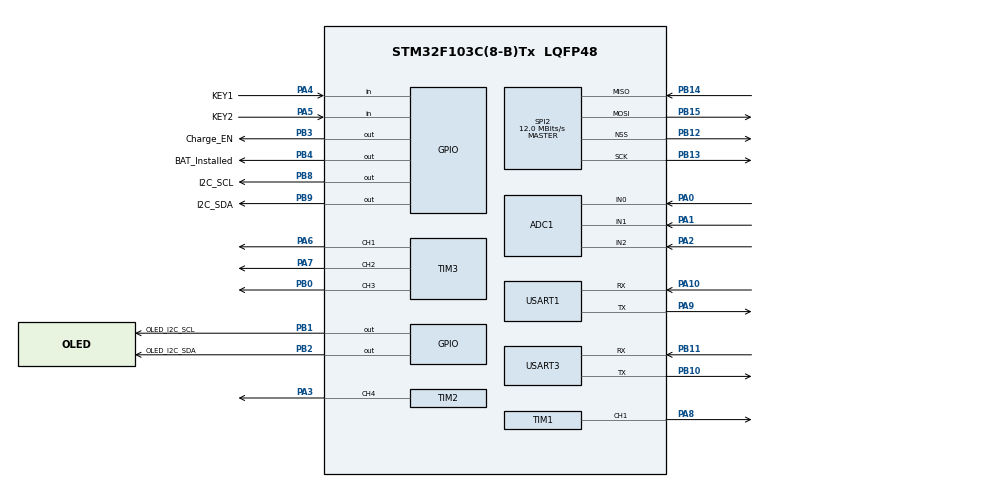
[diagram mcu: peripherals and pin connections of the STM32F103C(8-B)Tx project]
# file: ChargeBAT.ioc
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ADC1.Channel-0\#ChannelRegularConversion=ADC_CHANNEL_0
ADC1.Channel-1\#ChannelRegularConversion=ADC_CHANNEL_1
ADC1.Channel-2\#ChannelRegularConversion=ADC_CHANNEL_2
ADC1.ContinuousConvMode=DISABLE
ADC1.NbrOfConversion=3
ADC1.NbrOfConversionFlag=1
ADC1.Rank-0\#ChannelRegularConversion=1
ADC1.Rank-1\#ChannelRegularConversion=2
ADC1.Rank-2\#ChannelRegularConversion=3
ADC1.SamplingTime-0\#ChannelRegularConversion=ADC_SAMPLETIME_71CYCLES_5
ADC1.SamplingTime-1\#ChannelRegularConversion=ADC_SAMPLETIME_71CYCLES_5
ADC1.SamplingTime-2\#ChannelRegularConversion=ADC_SAMPLETIME_71CYCLES_5
ADC1.master=1
Dma.ADC1.3.Direction=DMA_PERIPH_TO_MEMORY
Dma.ADC1.3.Instance=DMA1_Channel1
Dma.ADC1.3.MemDataAlignment=DMA_MDATAALIGN_HALFWORD
Dma.ADC1.3.MemInc=DMA_MINC_ENABLE
Dma.ADC1.3.Mode=DMA_NORMAL
Dma.ADC1.3.PeriphDataAlignment=DMA_PDATAALIGN_HALFWORD
Dma.ADC1.3.PeriphInc=DMA_PINC_DISABLE
Dma.ADC1.3.Priority=DMA_PRIORITY_LOW
Dma.Request0=SPI2_TX
Dma.Request1=USART3_RX
Dma.Request2=USART1_TX
Dma.Request3=ADC1
Dma.SPI2_TX.0.Direction=DMA_MEMORY_TO_PERIPH
Dma.SPI2_TX.0.Instance=DMA1_Channel5
Dma.SPI2_TX.0.MemDataAlignment=DMA_MDATAALIGN_BYTE
Dma.SPI2_TX.0.MemInc=DMA_MINC_ENABLE
Dma.SPI2_TX.0.Mode=DMA_NORMAL
Dma.SPI2_TX.0.PeriphDataAlignment=DMA_PDATAALIGN_BYTE
Dma.SPI2_TX.0.PeriphInc=DMA_PINC_DISABLE
Dma.SPI2_TX.0.Priority=DMA_PRIORITY_LOW
Dma.USART1_TX.2.Direction=DMA_MEMORY_TO_PERIPH
Dma.USART1_TX.2.Instance=DMA1_Channel4
Dma.USART1_TX.2.MemDataAlignment=DMA_MDATAALIGN_BYTE
Dma.USART1_TX.2.MemInc=DMA_MINC_ENABLE
Dma.USART1_TX.2.Mode=DMA_NORMAL
Dma.USART1_TX.2.PeriphDataAlignment=DMA_PDATAALIGN_BYTE
Dma.USART1_TX.2.PeriphInc=DMA_PINC_DISABLE
Dma.USART1_TX.2.Priority=DMA_PRIORITY_LOW
Dma.USART3_RX.1.Direction=DMA_PERIPH_TO_MEMORY
Dma.USART3_RX.1.Instance=DMA1_Channel3
Dma.USART3_RX.1.MemDataAlignment=DMA_MDATAALIGN_BYTE
Dma.USART3_RX.1.MemInc=DMA_MINC_ENABLE
Dma.USART3_RX.1.Mode=DMA_NORMAL
Dma.USART3_RX.1.PeriphDataAlignment=DMA_PDATAALIGN_BYTE
Dma.USART3_RX.1.PeriphInc=DMA_PINC_DISABLE
Dma.USART3_RX.1.Priority=DMA_PRIORITY_LOW
Mcu.Family=STM32F1
Mcu.Name=STM32F103C(8-B)Tx
Mcu.Package=LQFP48
NVIC.ADC1_2_IRQn=true\:0\:0\:false\:false\:true\:true\:true\:true
NVIC.DMA1_Channel1_IRQn=true\:0\:0\:false\:false\:true\:false\:true\:true
NVIC.DMA1_Channel3_IRQn=true\:0\:0\:false\:false\:true\:false\:true\:true
NVIC.DMA1_Channel4_IRQn=true\:0\:0\:false\:false\:true\:false\:true\:true
NVIC.DMA1_Channel5_IRQn=true\:0\:0\:false\:false\:true\:false\:true\:true
NVIC.PriorityGroup=NVIC_PRIORITYGROUP_4
NVIC.TIM2_IRQn=true\:0\:0\:false\:false\:true\:true\:true\:true
NVIC.TIM4_IRQn=true\:0\:0\:false\:false\:true\:true\:true\:true
NVIC.USART3_IRQn=true\:0\:0\:false\:false\:true\:true\:true\:true
PA0-WKUP.Signal=ADCx_IN0
PA1.Signal=ADCx_IN1
PA10.Mode=Asynchronous
PA10.Signal=USART1_RX
PA11.Signal=USB_DM
PA13.Mode=Serial_Wire
PA13.Signal=SYS_JTMS-SWDIO
PA14.Mode=Serial_Wire
PA14.Signal=SYS_JTCK-SWCLK
PA2.Signal=ADCx_IN2
PA3.Signal=S_TIM2_CH4
PA4.GPIO_Label=KEY1
PA4.Signal=GPIO_Input
PA5.GPIO_Label=KEY2
PA5.Signal=GPIO_Input
PA6.Signal=S_TIM3_CH1
PA7.Signal=S_TIM3_CH2
PA8.Signal=S_TIM1_CH1
PA9.Mode=Asynchronous
PA9.Signal=USART1_TX
PB0.Signal=S_TIM3_CH3
PB1.GPIO_Label=OLED_I2C_SCL
PB1.GPIO_ModeDefaultOutputPP=GPIO_MODE_OUTPUT_OD
PB1.GPIO_PuPd=GPIO_NOPULL
PB1.Signal=GPIO_Output
PB10.Mode=Asynchronous
PB10.Signal=USART3_TX
PB11.Mode=Asynchronous
PB11.Signal=USART3_RX
PB12.Mode=NSS_Signal_Hard_Output
PB12.Signal=SPI2_NSS
PB13.Mode=Full_Duplex_Master
PB13.Signal=SPI2_SCK
PB14.Mode=Full_Duplex_Master
PB14.Signal=SPI2_MISO
PB15.Mode=Full_Duplex_Master
PB15.Signal=SPI2_MOSI
PB2.GPIO_Label=OLED_I2C_SDA
PB2.GPIO_ModeDefaultOutputPP=GPIO_MODE_OUTPUT_OD
PB2.GPIO_PuPd=GPIO_NOPULL
PB2.Signal=GPIO_Output
PB3.GPIO_Label=Charge_EN
PB3.Signal=GPIO_Output
PB4.GPIO_Label=BAT_Installed
PB4.Signal=GPIO_Output
PB8.GPIO_Label=I2C_SCL
PB8.GPIO_ModeDefaultOutputPP=GPIO_MODE_OUTPUT_OD
PB8.GPIO_PuPd=GPIO_NOPULL
PB8.Signal=GPIO_Output
PB9.GPIO_Label=I2C_SDA
PB9.GPIO_ModeDefaultOutputPP=GPIO_MODE_OUTPUT_OD
PB9.GPIO_PuPd=GPIO_NOPULL
PB9.Signal=GPIO_Output
PD0-OSC_IN.Mode=HSE-External-Oscillator
PD0-OSC_IN.Signal=RCC_OSC_IN
PD1-OSC_OUT.Mode=HSE-External-Oscillator
PD1-OSC_OUT.Signal=RCC_OSC_OUT
ProjectManager.HeapSize=0x200
ProjectManager.StackSize=0x400
ProjectManager.TargetToolchain=MDK-ARM V5.32
RCC.ADCPresc=RCC_ADCPCLK2_DIV4
RCC.AHBFreq_Value=48000000
RCC.APB1CLKDivider=RCC_HCLK_DIV2
RCC.APB1Freq_Value=24000000
RCC.APB1TimFreq_Value=48000000
RCC.APB2Freq_Value=48000000
RCC.APB2TimFreq_Value=48000000
RCC.HCLKFreq_Value=48000000
RCC.PLLMUL=RCC_PLL_MUL6
RCC.PLLSourceVirtual=RCC_PLLSOURCE_HSE
RCC.SYSCLKFreq_VALUE=48000000
RCC.SYSCLKSource=RCC_SYSCLKSOURCE_PLLCLK
RCC.USBFreq_Value=48000000
SH.ADCx_IN0.0=ADC1_IN0,IN0
SH.ADCx_IN1.0=ADC1_IN1,IN1
SH.ADCx_IN2.0=ADC1_IN2,IN2
SH.S_TIM1_CH1.0=TIM1_CH1,PWM Generation1 CH1
SH.S_TIM2_CH4.0=TIM2_CH4,PWM Generation4 CH4
SH.S_TIM3_CH1.0=TIM3_CH1,PWM Generation1 CH1
SH.S_TIM3_CH2.0=TIM3_CH2,PWM Generation2 CH2
SH.S_TIM3_CH3.0=TIM3_CH3,PWM Generation3 CH3
SPI2.CalculateBaudRate=12.0 MBits/s
SPI2.Direction=SPI_DIRECTION_2LINES
SPI2.Mode=SPI_MODE_MASTER
SPI2.VirtualNSS=VM_NSSHARD
SPI2.VirtualType=VM_MASTER
TIM1.AutoReloadPreload=TIM_AUTORELOAD_PRELOAD_ENABLE
TIM1.Channel-Output\ Compare2\ CH2=TIM_CHANNEL_2
TIM1.Channel-PWM\ Generation1\ CH1=TIM_CHANNEL_1
TIM1.Period=99
TIM1.Prescaler=7199
TIM1.Pulse-PWM\ Generation1\ CH1=49
TIM2.AutoReloadPreload=TIM_AUTORELOAD_PRELOAD_DISABLE
TIM2.Channel-PWM\ Generation4\ CH4=TIM_CHANNEL_4
TIM2.Period=65535
TIM2.Prescaler=0
TIM3.AutoReloadPreload=TIM_AUTORELOAD_PRELOAD_ENABLE
TIM3.Channel-PWM\ Generation1\ CH1=TIM_CHANNEL_1
TIM3.Channel-PWM\ Generation2\ CH2=TIM_CHANNEL_2
TIM3.Channel-PWM\ Generation3\ CH3=TIM_CHANNEL_3
TIM4.Channel-Output\ Compare1\ No\ Output=TIM_CHANNEL_1
TIM4.Period=99
TIM4.Prescaler=7199
USART1.VirtualMode=VM_ASYNC
USART3.VirtualMode=VM_ASYNC
VP_TIM1_VS_ClockSourceINT.Mode=Internal
VP_TIM3_VS_ClockSourceINT.Mode=Internal
VP_TIM4_VS_ClockSourceINT.Mode=Internal
VP_TIM4_VS_no_output1.Mode=Output Compare1 No Output
board=custom

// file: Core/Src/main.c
/* USER CODE BEGIN Header */
/**
  ******************************************************************************
  * @file           : main.c
  * @brief          : Main program body
  ******************************************************************************
  * @attention
  *
  * Copyright (c) 2026 STMicroelectronics.
  * All rights reserved.
  *
  * This software is licensed under terms that can be found in the LICENSE file
  * in the root directory of this software component.
  * If no LICENSE file comes with this software, it is provided AS-IS.
  *
  ******************************************************************************
  */
/* USER CODE END Header */
#include "main.h"
#include "adc.h"
#include "dma.h"
#include "spi.h"
#include "tim.h"
#include "usart.h"
#include "gpio.h"

#include "logo_128x64.h"
#include "i2c_soft.h"
#include "ch224.h"
#include "oled.h"
#include "tmp100.h"
#include "stdlib.h"
#include "stdio.h"
#include "string.h"
#include "parse_command.h"
#include "key.h"

#include "tws_bms.h"
#include "spi_flash_w25q128.h"

void SystemClock_Config(void);

/* USER CODE BEGIN 0 */

uint8_t hostData[128] = {0};
uint8_t rs485Data[128] = {0};
uint8_t UART1_RX_DMA_IDLE;
uint8_t UART3_RX_DMA_IDLE;
uint8_t ADC1_IDLE = 0;

char cLogo[] = "RoboParty USBC Charge Board.\n";
void hostCmdProcess(uint8_t * cmd, uint16_t len);

float CHRG_I = 0.000f, CHRG_V = 0.000f, BAT_V = 0.000f;
uint16_t adc_buffer0[3] = {0};
uint16_t adc_buffer1[3] = {0};
uint8_t ADC_BUF_SEL = 0;
uint16_t CHRG_PWR = 0;

env_secure_t * pEnvSecure;
uint8_t seq_idx = 0;

char     str_chrg_i[16], str_chrg_v[16], str_bat_v[16];
char     max_current[16];
char     strBmsSoc[6];
char     strBmsSoh[6];
char     strChrgPwr[3];
uint16_t BmsSoc[1] = {0};
uint16_t BmsSoh[1] = {0};
char     strTemp[16];
uint8_t  env_est_idx = 0;
float    mid_bat_volt = 0.0f;
float    mid_chrg_current = 0.0f;
float    mid_chrg_volt = 0.0f;
float    mid_temp = 0.0f;
float    temp = 0.0f;

uint8_t  BAT_INST = 0, IR_REC = 0;
uint8_t  lcd_rfsh_cnt = 0;
uint8_t  rcv_ir_flag;
uint16_t buzzer_act_cnt;
uint8_t  BMS_COM_ERR;
uint8_t  CLEAN_EXCP = 0;
uint8_t  CHRG_FULL;
// ??? printf ? USART3(???? huart3)
int fputc(int ch, FILE *f)
{
    // ????????
    HAL_UART_Transmit(&huart3, (uint8_t*)&ch, 1, HAL_MAX_DELAY);
    return ch;
}
/* USER CODE END 0 */

void EnvSecureOp()
{
    if((pEnvSecure->estimate_chrg_volt >= 32.0f) || (pEnvSecure->estimate_chrg_volt >= 5.5f && pEnvSecure->estimate_chrg_volt <= 16.0f) ||
       (pEnvSecure->estimate_bat_volt >= 55.0f) || (pEnvSecure->estimate_temp >= 80.0f) ||
       (pEnvSecure->estimate_chrg_current >= 6.0f) || (pEnvSecure->estimate_chrg_volt >= 16.0f && BmsSoc[0] == 100) ||
       ((BAT_INST == 0) && (IR_REC == 1))
       )
    {
        g_config.chg_en = 0;
        g_config.ictrl  = 0;
        g_config.r = 80;
        g_config.g = 0;
        g_config.b = 0;
        pEnvSecure->exception = 1;
        ApplyConfig();

        OLED_Clear();
        OLED_ShowString(0, 0, (uint8_t*)"Exception!", 16);
        OLED_ShowString(0, 2, (uint8_t*)"L-Press to EXIT!", 16);

    }
}

void LCD_DispRefresh();

int main(void)
{

	/* USER CODE BEGIN 1 */
//    SCB->VTOR = 0x08004000;
	/* USER CODE END 1 */

	/* MCU Configuration--------------------------------------------------------*/

	/* Reset of all peripherals, Initializes the Flash interface and the Systick. */
	HAL_Init();

	/* Configure the system clock */
	SystemClock_Config();

	/* Initialize all configured peripherals */
	MX_GPIO_Init();
	MX_DMA_Init();
	MX_ADC1_Init();

    MX_SPI2_Init();
	MX_TIM1_Init();
	MX_TIM3_Init();
	MX_USART3_UART_Init();
	MX_TIM2_Init();
	MX_USART1_UART_Init();
    MX_TIM4_Init();
	/* USER CODE BEGIN 2 */
    HAL_TIM_Base_Start_IT(&htim4);////KSY Scan

	if(LoadConfigFromFlash(&g_config) == 1)// No Saved Config data
	{
		g_config.b = 10;
		g_config.g = 10;
		g_config.r = 10;
		g_config.chg_en = 0;
		g_config.ictrl = 0;
        g_config.fan = 49;

		printf("Flash Empty, load default parameter");
	}
	else
	{
//		printf("Flash Cfg\r\nB:%d;G:%d;R:%d;I_CTRL:%d", g_config.b, g_config.g, g_config.r, g_config.ictrl);
	}
	ApplyConfig();
	HAL_Delay(1000);
	I2C_SOFT_INIT();
	OLED_Init();
//	OLED_Clear();
    pEnvSecure = malloc(sizeof(env_secure_t));

	uint8_t voltage_status = 0;
	uint16_t avs_volt =0;

    /* USER CODE END 2 */

  /* Infinite loop */
  /* USER CODE BEGIN WHILE */
//	float temperature = 0.0f;
	HAL_TIM_PWM_Start(&htim3, TIM_CHANNEL_1);
	HAL_TIM_PWM_Start(&htim3, TIM_CHANNEL_2);
	HAL_TIM_PWM_Start(&htim3, TIM_CHANNEL_3);
	HAL_TIM_PWM_Start(&htim2, TIM_CHANNEL_4);

//	HAL_TIM_PWM_Stop(&htim3, TIM_CHANNEL_1);
//	HAL_TIM_PWM_Stop(&htim3, TIM_CHANNEL_2);
//	HAL_TIM_PWM_Stop(&htim3, TIM_CHANNEL_3);
//	HAL_TIM_PWM_Stop(&htim2, TIM_CHANNEL_4);
//	__HAL_TIM_SET_COMPARE(&htim3, TIM_CHANNEL_1, 65000);//B
//	__HAL_TIM_SET_COMPARE(&htim3, TIM_CHANNEL_2, 65000);//R
//	__HAL_TIM_SET_COMPARE(&htim3, TIM_CHANNEL_3, 65000);//G
//	__HAL_TIM_SET_COMPARE(&htim2, TIM_CHANNEL_4, 2400);//DAC
	__HAL_TIM_SET_COMPARE(&htim1, TIM_CHANNEL_1, 49);//FAN
	HAL_TIM_PWM_Start(&htim1, TIM_CHANNEL_1);

//	HAL_Delay(1000);

	printf("%s;", cLogo);

	HAL_UARTEx_ReceiveToIdle_DMA(&huart3, hostData, 128);

	if (HAL_ADC_Start_DMA(&hadc1, (uint32_t*)adc_buffer0, 3) != HAL_OK)
	{
		Error_Handler();
	}

	uint8_t adaptInfo[48] = {0};

//	CH224_ReadAdaptorInfo(adaptInfo);
//	printf("AdaptInfo: %s\n", adaptInfo);
	CH224_I2C_Status * ch224_status = malloc(sizeof(CH224_I2C_Status));
	CH224_ReadAVS(&avs_volt);
//	CH224_ReadStatus(&voltage_status, ch224_status);

	float Max_I = 0;//ch224_status->Max_I * 0.05f;//50mA Unit
	float AVS_V = 0;//avs_volt * 0.1f;
	if (CH224_ReadStatus(&voltage_status, ch224_status) == 0)
	{
		Max_I = ch224_status->Max_I * 0.05f;//50mA Unit
		AVS_V = avs_volt * 0.1f;
	}
	else
	{
		OLED_ShowString(0, 3, (uint8_t*)"CH224 Err", 16);
	}

//    OLED_DrawBMP(0, 0, 128, 8, gImage_PD_PWR);
    OLED_DrawBMP(0, 0, 128, 8, gImage_SUM_INFO);
    uint8_t i_retry = 0;

    if(BAT_INST && IR_REC && CHRG_V >= 4.0f)
    {
        if(ReadBMS_SOC(BmsSoc))
            BMS_COM_ERR = 1;
        else
            sprintf(strBmsSoc, "%d", BmsSoc[0]);
        HAL_Delay(100);
        if(ReadBMS_SOH(BmsSoh))
            BMS_COM_ERR = 1;
        else
            sprintf(strBmsSoh, "%d", BmsSoh[0]);
    }
    else
    {
        BmsSoc[0] = 0;
        BmsSoh[0] = 0;
    }
	while (1)
	{
		if(UART3_RX_DMA_IDLE)
		{

			UART3_RX_DMA_IDLE = 0;
			uint16_t recv_len = 128 - huart3.RxXferCount;////128 - __HAL_DMA_GET_COUNTER(huart3.hdmarx);
			parse_command(hostData, recv_len);
		}
		if(hadc1.DMA_Handle->State == HAL_DMA_STATE_READY)
		{
			ADC1_IDLE = 0;
            CHRG_I = (float)adc_buffer0[0]/4095.f*3.3/0.4536;////gain=0.01*(49.9/1.1)=0.4536
			BAT_V = (float)adc_buffer0[1]/4095.f*3.3/0.0449;////gain=4.7/(47+4.7)=0.0909
			CHRG_V  = (float)adc_buffer0[2]/4095.f*3.3/0.0909;////gain=4.7/(100+4.7)=0.0449
            CHRG_PWR = CHRG_I * CHRG_V;
            sprintf(str_chrg_i, "%-3.1fA", CHRG_I);
            sprintf(str_chrg_v, "%-4.1fV", CHRG_V);
            sprintf(str_bat_v, "BAT_V: %-4.1fV", BAT_V);
			sprintf(max_current, "MAX_I: %.1fA", Max_I);
            if(env_est_idx == 2)
            {
                env_est_idx = 0;
                mid_bat_volt += BAT_V;
                mid_chrg_current += CHRG_I;
                mid_chrg_volt += CHRG_V;
                temp = TMP100_GetTemperature();

                pEnvSecure->estimate_bat_volt = mid_bat_volt / 3;
                pEnvSecure->estimate_chrg_current = mid_chrg_current / 3;
                pEnvSecure->estimate_chrg_volt = mid_chrg_volt / 3;
                pEnvSecure->estimate_temp = mid_temp / 3;
                mid_bat_volt = 0.0f;
                mid_chrg_current = 0.0f;
                mid_chrg_volt = 0.0f;
                mid_temp = 0.0f;
            }
            else
            {
                env_est_idx ++;
                mid_bat_volt += BAT_V;
                mid_chrg_current += CHRG_I;
                mid_chrg_volt += CHRG_V;
                temp = TMP100_GetTemperature();
                mid_temp += temp;
            }

            sprintf(strTemp, "%-4.1foC", temp);
			HAL_ADC_Start_DMA(&hadc1, (uint32_t*)adc_buffer0, 3);
		}

        if(CHRG_V >= 16.0f && g_config.chg_en == 1)//// <=5V, Close FAN
        {
            if(pEnvSecure->estimate_temp <= 50.0f)
                g_config.fan = 49;//__HAL_TIM_SET_COMPARE(&htim1, TIM_CHANNEL_1, 49);//FAN
            else if((pEnvSecure->estimate_temp > 50.0f) && (pEnvSecure->estimate_temp <= 70.0f))
                g_config.fan = 49 + (pEnvSecure->estimate_temp-50) * 2.5;
            else
                g_config.fan = 99;
        }
        else
            g_config.fan = 0;

        CH224_ReadAVS(&avs_volt);
        AVS_V = avs_volt * 0.1f;
        Max_I = CH224_ReadCurrent() * 0.05f;

//        printf("pEnvSecure->exception:%d", pEnvSecure->exception);
        if(CHRG_V >= 16.0f && BAT_INST && IR_REC && pEnvSecure->exception == 0)
        {
            g_config.ictrl = Max_I / 5.0f * 66 ;//70->5A, 0.95->0.95* 70 ;
            g_config.chg_en = 1;
        }
        else
        {
            g_config.ictrl = 0;
            g_config.chg_en = 0;
        }

//        if(BAT_INST ==0  && IR_REC ==0)
//        {
//            printf("BAT UNINSTALL");
//            HAL_GPIO_WritePin(BUZZER_GPIO_Port, BUZZER_Pin, GPIO_PIN_SET);
//            HAL_Delay(3000);
//            HAL_GPIO_WritePin(BUZZER_GPIO_Port, BUZZER_Pin, GPIO_PIN_RESET);
//        }

        ApplyConfig();

        if(BAT_INST && IR_REC && CHRG_V >= 4.0f)// && BMS_COM_ERR == 0
        {
            if(ReadBMS_SOC(BmsSoc) == 0)
                sprintf(strBmsSoc, "%d", BmsSoc[0]);
            else
                BMS_COM_ERR = 1;
            HAL_Delay(100);
            if(ReadBMS_SOH(BmsSoh) == 0)
                sprintf(strBmsSoh, "%d", BmsSoh[0]);
            else
                BMS_COM_ERR = 1;
            HAL_Delay(100);
        }
        else
            BmsSoc[0] = 0;

            //------Open IR_EM --------------//
        HAL_GPIO_WritePin(IR_EM_GPIO_Port, IR_EM_Pin, GPIO_PIN_SET);
        HAL_Delay(10);
        IR_REC   = HAL_GPIO_ReadPin(IR_REC_GPIO_Port, IR_REC_Pin)^0x01;
//        IR_REC   = 1;
        HAL_GPIO_WritePin(IR_EM_GPIO_Port, IR_EM_Pin, GPIO_PIN_RESET);

        EnvSecureOp();
        if(pEnvSecure->exception == 1 && CLEAN_EXCP == 0)
        {
            CLEAN_EXCP = 1;
            BmsSoc[0] = 0;
            printf("est_chrg_v: %-4.1f\t", pEnvSecure->estimate_chrg_volt);
            printf("est_bat_v: %-4.1f\t", pEnvSecure->estimate_bat_volt);
            printf("est_temp: %-3.1f\t", pEnvSecure->estimate_temp);
            printf("est_chrg_i: %-2.1f\n", pEnvSecure->estimate_chrg_current);

            HAL_GPIO_WritePin(BUZZER_GPIO_Port, BUZZER_Pin, GPIO_PIN_SET);
            HAL_Delay(1500);
            HAL_GPIO_WritePin(BUZZER_GPIO_Port, BUZZER_Pin, GPIO_PIN_RESET);
        }

//        if(BAT_INST && IR_REC && BMS_COM_ERR == 0 && BmsSoc[0] != 100 && CHRG_V <= 16.0f)
//        {
//
//        }
        HAL_Delay(300);
	}
  /* USER CODE END 3 */
}

void HAL_TIM_PeriodElapsedCallback(TIM_HandleTypeDef *htim)
{
    if (htim->Instance == TIM4)
    {
        if(htim->Channel == TIM_CHANNEL_1)
        {
            KEY_Scan();   // Scan Key Event, short press, double click, long press

            BAT_INST = HAL_GPIO_ReadPin(BAT_INST_GPIO_Port, BAT_INST_Pin)^0x01;
            ////-------Refresh OLED Display---------////
            if(lcd_rfsh_cnt == 20 && pEnvSecure->exception == 0)
            {
                lcd_rfsh_cnt = 0;
                LCD_DispRefresh();
            }
            else
                lcd_rfsh_cnt ++;
            ////----- long press key -------////
            if(KEY_LONG_EVENT)
            {
                KEY_LONG_EVENT = 0;
                CLEAN_EXCP = 0;
                pEnvSecure->exception = 0;
                KEY1_VAL = 1;
                OLED_Clear();
                OLED_DrawBMP(0, 0, 128, 8, gImage_SUM_INFO);

            }
        }
        ////-------- Channel 2 for System Exception ----------------////
//        if(htim->Channel == TIM_CHANNEL_2)
//        {
//            EnvSecureOp();
//            if(pEnvSecure->exception == 1)
//            {
//                if(buzzer_act_cnt != 300)
//                {
//                    buzzer_act_cnt ++;
//                    HAL_GPIO_WritePin(BUZZER_GPIO_Port, BUZZER_Pin, GPIO_PIN_SET);
//                }
//                else
//                    HAL_GPIO_WritePin(BUZZER_GPIO_Port, BUZZER_Pin, GPIO_PIN_RESET);
//            }
//            else
//                buzzer_act_cnt = 0;
//        }
    }
}
void HAL_ADC_ConvCpltCallback(ADC_HandleTypeDef* hadc)
{
    if(hadc == &hadc1)
	{
//        pEnvSecure -> lpf_current += 0.1*(CHRG_I - pEnvSecure -> lpf_current);
//        pEnvSecure -> lpf_voltage += 0.1*(CHRG_V - pEnvSecure -> lpf_voltage);

		ADC1_IDLE = 1;
	}
}

void HAL_UARTEx_RxEventCallback(UART_HandleTypeDef *huart, uint16_t Size)
{
	if(huart == &huart3)
	{
		HAL_UARTEx_ReceiveToIdle_DMA(&huart3, hostData, 128);

		UART3_RX_DMA_IDLE = 1;
	}
	else if(huart == &huart1)
	{
		HAL_UARTEx_ReceiveToIdle_DMA(huart, rs485Data, 128);
		UART1_RX_DMA_IDLE = 1;
	}
}

void SystemClock_Config(void)
{
	RCC_OscInitTypeDef RCC_OscInitStruct = {0};
	RCC_ClkInitTypeDef RCC_ClkInitStruct = {0};
	RCC_PeriphCLKInitTypeDef PeriphClkInit = {0};

	/** Initializes the RCC Oscillators according to the specified parameters
	* in the RCC_OscInitTypeDef structure.
	*/
	RCC_OscInitStruct.OscillatorType = RCC_OSCILLATORTYPE_HSE;
	RCC_OscInitStruct.HSEState = RCC_HSE_ON;
	RCC_OscInitStruct.HSEPredivValue = RCC_HSE_PREDIV_DIV1;
	RCC_OscInitStruct.HSIState = RCC_HSI_ON;
	RCC_OscInitStruct.PLL.PLLState = RCC_PLL_ON;
	RCC_OscInitStruct.PLL.PLLSource = RCC_PLLSOURCE_HSE;
  RCC_OscInitStruct.PLL.PLLMUL = RCC_PLL_MUL9;
	if (HAL_RCC_OscConfig(&RCC_OscInitStruct) != HAL_OK)
	{
	Error_Handler();
	}

	/** Initializes the CPU, AHB and APB buses clocks
	*/
	RCC_ClkInitStruct.ClockType = RCC_CLOCKTYPE_HCLK|RCC_CLOCKTYPE_SYSCLK
							  |RCC_CLOCKTYPE_PCLK1|RCC_CLOCKTYPE_PCLK2;
	RCC_ClkInitStruct.SYSCLKSource = RCC_SYSCLKSOURCE_PLLCLK;
	RCC_ClkInitStruct.AHBCLKDivider = RCC_SYSCLK_DIV1;
	RCC_ClkInitStruct.APB1CLKDivider = RCC_HCLK_DIV2;
	RCC_ClkInitStruct.APB2CLKDivider = RCC_HCLK_DIV1;

  if (HAL_RCC_ClockConfig(&RCC_ClkInitStruct, FLASH_LATENCY_2) != HAL_OK)
	{
	Error_Handler();
	}
	PeriphClkInit.PeriphClockSelection = RCC_PERIPHCLK_ADC;
  PeriphClkInit.AdcClockSelection = RCC_ADCPCLK2_DIV6;
	if (HAL_RCCEx_PeriphCLKConfig(&PeriphClkInit) != HAL_OK)
	{
	Error_Handler();
	}
}

void Error_Handler(void)
{
	__disable_irq();
	while (1)
	{
	}
}

void LCD_DispRefresh()
{
    if(KEY1_VAL)
    {
        ///---voltage display-----//
        if(str_chrg_v[2] == '.')
        {
            OLED_DrawBMP(19, 6, 35, 7, &gImage_12x12[str_chrg_v[0]-'0'][0]);
            OLED_DrawBMP(19, 5, 35, 6, &gImage_12x12[str_chrg_v[1]-'0'][0]);
            OLED_DrawBMP(19, 4, 35, 5, &gImage_12x12[10][0]);
            OLED_DrawBMP(19, 3, 35, 4, &gImage_12x12[str_chrg_v[3]-'0'][0]);
        }
        else
        {
            OLED_DrawBMP(19, 6, 35, 7, &gImage_12x12[11][0]);
            OLED_DrawBMP(19, 5, 35, 6, &gImage_12x12[str_chrg_v[0]-'0'][0]);
            OLED_DrawBMP(19, 4, 35, 5, &gImage_12x12[10][0]);
            OLED_DrawBMP(19, 3, 35, 4, &gImage_12x12[str_chrg_v[2]-'0'][0]);
        }
        ///---current display----//
        OLED_DrawBMP(49, 5, 65, 6, &gImage_12x12[str_chrg_i[0]-'0'][0]);
        OLED_DrawBMP(49, 4, 65, 5, &gImage_12x12[10][0]);
        OLED_DrawBMP(49, 3, 65, 4, &gImage_12x12[str_chrg_i[2]-'0'][0]);
//			OLED_ShowString(0, 0, (uint8_t*)max_current, 16);
        //OLED_ShowFloat(0, 2, AVS_V, 1, 16);

        if(strTemp[2] == '.')
        {
            OLED_DrawBMP(98, 6, 114, 7, &gImage_BBWW[strTemp[0]-'0'][0]);
            OLED_DrawBMP(98, 5, 114, 6, &gImage_BBWW[strTemp[1]-'0'][0]);
            OLED_DrawBMP(98, 4, 114, 5, &gImage_BBWW[10][0]);
            OLED_DrawBMP(98, 3, 114, 4, &gImage_BBWW[strTemp[3]-'0'][0]);
        }
        else
        {
            OLED_DrawBMP(98, 6, 114, 7, &gImage_BBWW[11][0]);
            OLED_DrawBMP(98, 5, 114, 6, &gImage_BBWW[strTemp[0]-'0'][0]);
            OLED_DrawBMP(98, 4, 114, 5, &gImage_BBWW[10][0]);
            OLED_DrawBMP(98, 3, 114, 4, &gImage_BBWW[strTemp[2]-'0'][0]);
        }
        OLED_DrawBMP(98, 5, 114, 6, &gImage_BBWW[strTemp[1]-'0'][0]);
        OLED_DrawBMP(98, 4, 114, 5, &gImage_BBWW[10][0]);
        OLED_DrawBMP(98, 3, 114, 4, &gImage_BBWW[strTemp[3]-'0'][0]);
    }
    else
    {

        if(BmsSoc[0] == 100)
        {
            OLED_DrawBMP(22, 5, 38, 6, &gImage_BBWW[strBmsSoc[0]-'0'][0]);
            OLED_DrawBMP(22, 4, 38, 5, &gImage_BBWW[strBmsSoc[1]-'0'][0]);
            OLED_DrawBMP(22, 3, 38, 4, &gImage_BBWW[strBmsSoc[2]-'0'][0]);
        }
        else
        {
            OLED_DrawBMP(22, 5, 38, 6, &gImage_BBWW[11][0]);
            OLED_DrawBMP(22, 4, 38, 5, &gImage_BBWW[strBmsSoc[0]-'0'][0]);
            OLED_DrawBMP(22, 3, 38, 4, &gImage_BBWW[strBmsSoc[1]-'0'][0]);
        }
        sprintf(strChrgPwr, "%d", CHRG_PWR);
        if(CHRG_PWR / 100)
        {
            OLED_DrawBMP(96, 5, 112, 6, &gImage_12x12[strChrgPwr[0]-'0'][0]);
            OLED_DrawBMP(96, 4, 112, 5, &gImage_12x12[strChrgPwr[1]-'0'][0]);
            OLED_DrawBMP(96, 3, 112, 4, &gImage_12x12[strChrgPwr[2]-'0'][0]);
        }
        else if(CHRG_PWR / 10)
        {
            OLED_DrawBMP(96, 5, 112, 6, &gImage_12x12[11][0]);
            OLED_DrawBMP(96, 4, 112, 5, &gImage_12x12[strChrgPwr[0]-'0'][0]);
            OLED_DrawBMP(96, 3, 112, 4, &gImage_12x12[strChrgPwr[1]-'0'][0]);
        }
        else
        {
            OLED_DrawBMP(96, 5, 112, 6, &gImage_12x12[11][0]);
            OLED_DrawBMP(96, 4, 112, 5, &gImage_12x12[11][0]);
            OLED_DrawBMP(96, 3, 112, 4, &gImage_12x12[strChrgPwr[0]-'0'][0]);
        }

//            OLED_ShowString(0, 0, (uint8_t*)str_chrg_i, 16);
//            OLED_ShowString(0, 2, (uint8_t*)str_chrg_v, 16);
//            OLED_ShowString(0, 4, (uint8_t*)str_bat_v, 16);
//            OLED_ShowString(0, 6, (uint8_t*)strTemp, 16);
//            printf("CHARGE_I: %s",str_chrg_i);
//            printf("CHARGE_V: %s", str_chrg_v);
//				printf("BAT_V: %s", str_bat_v);
    }

    if(KEY1_EVENT)
    {
        KEY1_EVENT = 0;
        KEY1_VAL = !KEY1_VAL;
//            printf("single click");
        OLED_Clear();
        if(KEY1_VAL)
            OLED_DrawBMP(0, 0, 128, 8, gImage_SUM_INFO);
        else
            OLED_DrawBMP(0, 0, 128, 8, gImage_PD_PWR);
    }
    else if(KEY2_EVENT)
    {
        KEY2_EVENT = 0;
        KEY2_VAL = !KEY2_VAL;
//            printf("double click");
        OLED_SetDirection(KEY2_VAL);
        OLED_Clear();
        if(KEY1_VAL)
            OLED_DrawBMP(0, 0, 128, 8, gImage_SUM_INFO);
        else
            OLED_DrawBMP(0, 0, 128, 8, gImage_PD_PWR);
    }

}
